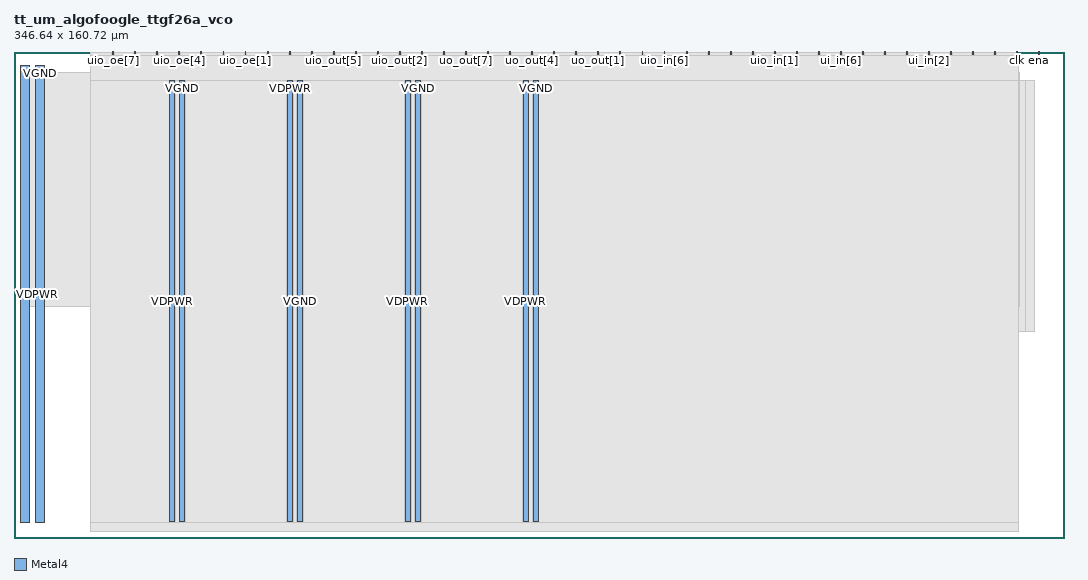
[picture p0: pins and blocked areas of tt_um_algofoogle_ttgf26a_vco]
MACRO tt_um_algofoogle_ttgf26a_vco
  CLASS BLOCK ;
  FOREIGN tt_um_algofoogle_ttgf26a_vco ;
  ORIGIN 0.000 0.000 ;
  SIZE 346.640 BY 160.720 ;
  PIN clk
    DIRECTION INPUT ;
    USE SIGNAL ;
    PORT
      LAYER Metal4 ;
        RECT 331.090 159.720 331.390 160.720 ;
    END
  END clk
  PIN ena
    DIRECTION INPUT ;
    USE SIGNAL ;
    PORT
      LAYER Metal4 ;
        RECT 338.370 159.720 338.670 160.720 ;
    END
  END ena
  PIN rst_n
    DIRECTION INPUT ;
    USE SIGNAL ;
    ANTENNAGATEAREA 0.396000 ;
    PORT
      LAYER Metal4 ;
        RECT 323.810 159.720 324.110 160.720 ;
    END
  END rst_n
  PIN ui_in[0]
    DIRECTION INPUT ;
    USE SIGNAL ;
    ANTENNAGATEAREA 0.853500 ;
    PORT
      LAYER Metal4 ;
        RECT 316.530 159.720 316.830 160.720 ;
    END
  END ui_in[0]
  PIN ui_in[1]
    DIRECTION INPUT ;
    USE SIGNAL ;
    ANTENNAGATEAREA 0.853500 ;
    PORT
      LAYER Metal4 ;
        RECT 309.250 159.720 309.550 160.720 ;
    END
  END ui_in[1]
  PIN ui_in[2]
    DIRECTION INPUT ;
    USE SIGNAL ;
    ANTENNAGATEAREA 0.853500 ;
    PORT
      LAYER Metal4 ;
        RECT 301.970 159.720 302.270 160.720 ;
    END
  END ui_in[2]
  PIN ui_in[3]
    DIRECTION INPUT ;
    USE SIGNAL ;
    ANTENNAGATEAREA 0.853500 ;
    PORT
      LAYER Metal4 ;
        RECT 294.690 159.720 294.990 160.720 ;
    END
  END ui_in[3]
  PIN ui_in[4]
    DIRECTION INPUT ;
    USE SIGNAL ;
    ANTENNAGATEAREA 0.853500 ;
    PORT
      LAYER Metal4 ;
        RECT 287.410 159.720 287.710 160.720 ;
    END
  END ui_in[4]
  PIN ui_in[5]
    DIRECTION INPUT ;
    USE SIGNAL ;
    ANTENNAGATEAREA 0.853500 ;
    PORT
      LAYER Metal4 ;
        RECT 280.130 159.720 280.430 160.720 ;
    END
  END ui_in[5]
  PIN ui_in[6]
    DIRECTION INPUT ;
    USE SIGNAL ;
    ANTENNAGATEAREA 0.853500 ;
    PORT
      LAYER Metal4 ;
        RECT 272.850 159.720 273.150 160.720 ;
    END
  END ui_in[6]
  PIN ui_in[7]
    DIRECTION INPUT ;
    USE SIGNAL ;
    ANTENNAGATEAREA 0.853500 ;
    PORT
      LAYER Metal4 ;
        RECT 265.570 159.720 265.870 160.720 ;
    END
  END ui_in[7]
  PIN uio_in[0]
    DIRECTION INPUT ;
    USE SIGNAL ;
    ANTENNAGATEAREA 0.853500 ;
    PORT
      LAYER Metal4 ;
        RECT 258.290 159.720 258.590 160.720 ;
    END
  END uio_in[0]
  PIN uio_in[1]
    DIRECTION INPUT ;
    USE SIGNAL ;
    PORT
      LAYER Metal4 ;
        RECT 251.010 159.720 251.310 160.720 ;
    END
  END uio_in[1]
  PIN uio_in[2]
    DIRECTION INPUT ;
    USE SIGNAL ;
    PORT
      LAYER Metal4 ;
        RECT 243.730 159.720 244.030 160.720 ;
    END
  END uio_in[2]
  PIN uio_in[3]
    DIRECTION INPUT ;
    USE SIGNAL ;
    PORT
      LAYER Metal4 ;
        RECT 236.450 159.720 236.750 160.720 ;
    END
  END uio_in[3]
  PIN uio_in[4]
    DIRECTION INPUT ;
    USE SIGNAL ;
    PORT
      LAYER Metal4 ;
        RECT 229.170 159.720 229.470 160.720 ;
    END
  END uio_in[4]
  PIN uio_in[5]
    DIRECTION INPUT ;
    USE SIGNAL ;
    PORT
      LAYER Metal4 ;
        RECT 221.890 159.720 222.190 160.720 ;
    END
  END uio_in[5]
  PIN uio_in[6]
    DIRECTION INPUT ;
    USE SIGNAL ;
    PORT
      LAYER Metal4 ;
        RECT 214.610 159.720 214.910 160.720 ;
    END
  END uio_in[6]
  PIN uio_in[7]
    DIRECTION INPUT ;
    USE SIGNAL ;
    PORT
      LAYER Metal4 ;
        RECT 207.330 159.720 207.630 160.720 ;
    END
  END uio_in[7]
  PIN uio_oe[0]
    DIRECTION OUTPUT ;
    USE SIGNAL ;
    ANTENNADIFFAREA 0.290400 ;
    PORT
      LAYER Metal4 ;
        RECT 83.570 159.720 83.870 160.720 ;
    END
  END uio_oe[0]
  PIN uio_oe[1]
    DIRECTION OUTPUT ;
    USE SIGNAL ;
    ANTENNADIFFAREA 0.290400 ;
    PORT
      LAYER Metal4 ;
        RECT 76.290 159.720 76.590 160.720 ;
    END
  END uio_oe[1]
  PIN uio_oe[2]
    DIRECTION OUTPUT ;
    USE SIGNAL ;
    ANTENNADIFFAREA 0.396000 ;
    PORT
      LAYER Metal4 ;
        RECT 69.010 159.720 69.310 160.720 ;
    END
  END uio_oe[2]
  PIN uio_oe[3]
    DIRECTION OUTPUT ;
    USE SIGNAL ;
    ANTENNADIFFAREA 0.396000 ;
    PORT
      LAYER Metal4 ;
        RECT 61.730 159.720 62.030 160.720 ;
    END
  END uio_oe[3]
  PIN uio_oe[4]
    DIRECTION OUTPUT ;
    USE SIGNAL ;
    ANTENNADIFFAREA 0.396000 ;
    PORT
      LAYER Metal4 ;
        RECT 54.450 159.720 54.750 160.720 ;
    END
  END uio_oe[4]
  PIN uio_oe[5]
    DIRECTION OUTPUT ;
    USE SIGNAL ;
    ANTENNADIFFAREA 0.396000 ;
    PORT
      LAYER Metal4 ;
        RECT 47.170 159.720 47.470 160.720 ;
    END
  END uio_oe[5]
  PIN uio_oe[6]
    DIRECTION OUTPUT ;
    USE SIGNAL ;
    ANTENNADIFFAREA 0.396000 ;
    PORT
      LAYER Metal4 ;
        RECT 39.890 159.720 40.190 160.720 ;
    END
  END uio_oe[6]
  PIN uio_oe[7]
    DIRECTION OUTPUT ;
    USE SIGNAL ;
    ANTENNADIFFAREA 0.396000 ;
    PORT
      LAYER Metal4 ;
        RECT 32.610 159.720 32.910 160.720 ;
    END
  END uio_oe[7]
  PIN uio_out[0]
    DIRECTION OUTPUT ;
    USE SIGNAL ;
    ANTENNADIFFAREA 0.290400 ;
    PORT
      LAYER Metal4 ;
        RECT 141.810 159.720 142.110 160.720 ;
    END
  END uio_out[0]
  PIN uio_out[1]
    DIRECTION OUTPUT ;
    USE SIGNAL ;
    ANTENNADIFFAREA 0.290400 ;
    PORT
      LAYER Metal4 ;
        RECT 134.530 159.720 134.830 160.720 ;
    END
  END uio_out[1]
  PIN uio_out[2]
    DIRECTION OUTPUT ;
    USE SIGNAL ;
    ANTENNADIFFAREA 12.404799 ;
    PORT
      LAYER Metal4 ;
        RECT 127.250 159.720 127.550 160.720 ;
    END
  END uio_out[2]
  PIN uio_out[3]
    DIRECTION OUTPUT ;
    USE SIGNAL ;
    ANTENNAGATEAREA 8.434000 ;
    ANTENNADIFFAREA 3.642000 ;
    PORT
      LAYER Metal4 ;
        RECT 119.970 159.720 120.270 160.720 ;
    END
  END uio_out[3]
  PIN uio_out[4]
    DIRECTION OUTPUT ;
    USE SIGNAL ;
    ANTENNAGATEAREA 7.250000 ;
    ANTENNADIFFAREA 3.642000 ;
    PORT
      LAYER Metal4 ;
        RECT 112.690 159.720 112.990 160.720 ;
    END
  END uio_out[4]
  PIN uio_out[5]
    DIRECTION OUTPUT ;
    USE SIGNAL ;
    ANTENNAGATEAREA 8.717000 ;
    ANTENNADIFFAREA 3.276000 ;
    PORT
      LAYER Metal4 ;
        RECT 105.410 159.720 105.710 160.720 ;
    END
  END uio_out[5]
  PIN uio_out[6]
    DIRECTION OUTPUT ;
    USE SIGNAL ;
    ANTENNAGATEAREA 7.081000 ;
    ANTENNADIFFAREA 3.276000 ;
    PORT
      LAYER Metal4 ;
        RECT 98.130 159.720 98.430 160.720 ;
    END
  END uio_out[6]
  PIN uio_out[7]
    DIRECTION OUTPUT ;
    USE SIGNAL ;
    ANTENNAGATEAREA 2.560500 ;
    ANTENNADIFFAREA 3.276000 ;
    PORT
      LAYER Metal4 ;
        RECT 90.850 159.720 91.150 160.720 ;
    END
  END uio_out[7]
  PIN uo_out[0]
    DIRECTION OUTPUT ;
    USE SIGNAL ;
    ANTENNADIFFAREA 0.290400 ;
    PORT
      LAYER Metal4 ;
        RECT 200.050 159.720 200.350 160.720 ;
    END
  END uo_out[0]
  PIN uo_out[1]
    DIRECTION OUTPUT ;
    USE SIGNAL ;
    ANTENNADIFFAREA 0.290400 ;
    PORT
      LAYER Metal4 ;
        RECT 192.770 159.720 193.070 160.720 ;
    END
  END uo_out[1]
  PIN uo_out[2]
    DIRECTION OUTPUT ;
    USE SIGNAL ;
    ANTENNADIFFAREA 0.290400 ;
    PORT
      LAYER Metal4 ;
        RECT 185.490 159.720 185.790 160.720 ;
    END
  END uo_out[2]
  PIN uo_out[3]
    DIRECTION OUTPUT ;
    USE SIGNAL ;
    ANTENNADIFFAREA 0.290400 ;
    PORT
      LAYER Metal4 ;
        RECT 178.210 159.720 178.510 160.720 ;
    END
  END uo_out[3]
  PIN uo_out[4]
    DIRECTION OUTPUT ;
    USE SIGNAL ;
    ANTENNADIFFAREA 0.290400 ;
    PORT
      LAYER Metal4 ;
        RECT 170.930 159.720 171.230 160.720 ;
    END
  END uo_out[4]
  PIN uo_out[5]
    DIRECTION OUTPUT ;
    USE SIGNAL ;
    ANTENNADIFFAREA 0.290400 ;
    PORT
      LAYER Metal4 ;
        RECT 163.650 159.720 163.950 160.720 ;
    END
  END uo_out[5]
  PIN uo_out[6]
    DIRECTION OUTPUT ;
    USE SIGNAL ;
    ANTENNADIFFAREA 0.290400 ;
    PORT
      LAYER Metal4 ;
        RECT 156.370 159.720 156.670 160.720 ;
    END
  END uo_out[6]
  PIN uo_out[7]
    DIRECTION OUTPUT ;
    USE SIGNAL ;
    ANTENNADIFFAREA 0.290400 ;
    PORT
      LAYER Metal4 ;
        RECT 149.090 159.720 149.390 160.720 ;
    END
  END uo_out[7]
  PIN VDPWR
    DIRECTION INOUT ;
    USE POWER ;
    PORT
      LAYER Metal4 ;
        RECT 2.000 5.000 5.000 156.000 ;
    END
  END VDPWR
  PIN VGND
    DIRECTION INOUT ;
    USE GROUND ;
    PORT
      LAYER Metal4 ;
        RECT 7.000 5.000 10.000 156.000 ;
    END
  END VGND
  PIN VDPWR
    DIRECTION INOUT ;
    USE POWER ;
    PORT
      LAYER Metal4 ;
        RECT 51.480 5.420 53.080 150.900 ;
    END
  END VDPWR
  PIN VDPWR
    DIRECTION INOUT ;
    USE POWER ;
    PORT
      LAYER Metal4 ;
        RECT 90.350 5.420 91.950 150.900 ;
    END
  END VDPWR
  PIN VDPWR
    DIRECTION INOUT ;
    USE POWER ;
    PORT
      LAYER Metal4 ;
        RECT 129.220 5.420 130.820 150.900 ;
    END
  END VDPWR
  PIN VDPWR
    DIRECTION INOUT ;
    USE POWER ;
    PORT
      LAYER Metal4 ;
        RECT 168.090 5.420 169.690 150.900 ;
    END
  END VDPWR
  PIN VGND
    DIRECTION INOUT ;
    USE GROUND ;
    PORT
      LAYER Metal4 ;
        RECT 171.390 5.420 172.990 150.900 ;
    END
  END VGND
  PIN VGND
    DIRECTION INOUT ;
    USE GROUND ;
    PORT
      LAYER Metal4 ;
        RECT 132.520 5.420 134.120 150.900 ;
    END
  END VGND
  PIN VGND
    DIRECTION INOUT ;
    USE GROUND ;
    PORT
      LAYER Metal4 ;
        RECT 93.650 5.420 95.250 150.900 ;
    END
  END VGND
  PIN VGND
    DIRECTION INOUT ;
    USE GROUND ;
    PORT
      LAYER Metal4 ;
        RECT 54.780 5.420 56.380 150.900 ;
    END
  END VGND
  OBS
      LAYER Nwell ;
        RECT 33.030 68.250 336.810 151.030 ;
      LAYER Metal1 ;
        RECT 35.960 68.250 333.880 151.050 ;
      LAYER Metal2 ;
        RECT 37.780 68.250 331.500 153.870 ;
      LAYER Metal3 ;
        RECT 2.000 76.550 332.000 153.820 ;
      LAYER Metal4 ;
        RECT 25.100 159.420 32.310 160.200 ;
        RECT 33.210 159.420 39.590 160.200 ;
        RECT 40.490 159.420 46.870 160.200 ;
        RECT 47.770 159.420 54.150 160.200 ;
        RECT 55.050 159.420 61.430 160.200 ;
        RECT 62.330 159.420 68.710 160.200 ;
        RECT 69.610 159.420 75.990 160.200 ;
        RECT 76.890 159.420 83.270 160.200 ;
        RECT 84.170 159.420 90.550 160.200 ;
        RECT 91.450 159.420 97.830 160.200 ;
        RECT 98.730 159.420 105.110 160.200 ;
        RECT 106.010 159.420 112.390 160.200 ;
        RECT 113.290 159.420 119.670 160.200 ;
        RECT 120.570 159.420 126.950 160.200 ;
        RECT 127.850 159.420 134.230 160.200 ;
        RECT 135.130 159.420 141.510 160.200 ;
        RECT 142.410 159.420 148.790 160.200 ;
        RECT 149.690 159.420 156.070 160.200 ;
        RECT 156.970 159.420 163.350 160.200 ;
        RECT 164.250 159.420 170.630 160.200 ;
        RECT 171.530 159.420 177.910 160.200 ;
        RECT 178.810 159.420 185.190 160.200 ;
        RECT 186.090 159.420 192.470 160.200 ;
        RECT 193.370 159.420 199.750 160.200 ;
        RECT 200.650 159.420 207.030 160.200 ;
        RECT 207.930 159.420 214.310 160.200 ;
        RECT 215.210 159.420 221.590 160.200 ;
        RECT 222.490 159.420 228.870 160.200 ;
        RECT 229.770 159.420 236.150 160.200 ;
        RECT 237.050 159.420 243.430 160.200 ;
        RECT 244.330 159.420 250.710 160.200 ;
        RECT 251.610 159.420 257.990 160.200 ;
        RECT 258.890 159.420 265.270 160.200 ;
        RECT 266.170 159.420 272.550 160.200 ;
        RECT 273.450 159.420 279.830 160.200 ;
        RECT 280.730 159.420 287.110 160.200 ;
        RECT 288.010 159.420 294.390 160.200 ;
        RECT 295.290 159.420 301.670 160.200 ;
        RECT 302.570 159.420 308.950 160.200 ;
        RECT 309.850 159.420 316.230 160.200 ;
        RECT 317.130 159.420 323.510 160.200 ;
        RECT 324.410 159.420 330.790 160.200 ;
        RECT 25.100 151.200 331.640 159.420 ;
        RECT 25.100 5.120 51.180 151.200 ;
        RECT 53.380 5.120 54.480 151.200 ;
        RECT 56.680 5.120 90.050 151.200 ;
        RECT 92.250 5.120 93.350 151.200 ;
        RECT 95.550 5.120 128.920 151.200 ;
        RECT 131.120 5.120 132.220 151.200 ;
        RECT 134.420 5.120 167.790 151.200 ;
        RECT 169.990 5.120 171.090 151.200 ;
        RECT 173.290 5.120 331.640 151.200 ;
        RECT 25.100 2.200 331.640 5.120 ;
  END
END tt_um_algofoogle_ttgf26a_vco
END LIBRARY

